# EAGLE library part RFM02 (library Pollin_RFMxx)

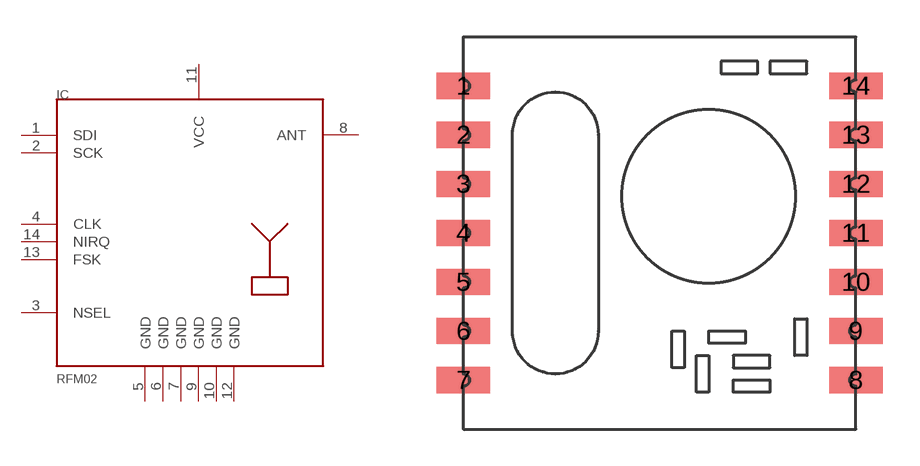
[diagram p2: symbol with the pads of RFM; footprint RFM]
Designator prefix IC

## RFM02  [RFM]
1  SDI
2  SCK
3  NSEL
4  CLK
5  GND
6  GND  pwr
7  GND  pwr
8  ANT  out
9  GND
10  GND
11  VCC  pwr
12  GND
13  FSK
14  NIRQ

## Footprint RFM (pad centres in mm)
smd 2.184 x 1.067: 1 0,14; 2 0,12; 3 0,10; 4 0,8; 5 0,6; 6 0,4; 7 0,2; 8 16,2; 9 16,4; 10 16,6; 11 16,8; 12 16,10; 13 16,12; 14 16,14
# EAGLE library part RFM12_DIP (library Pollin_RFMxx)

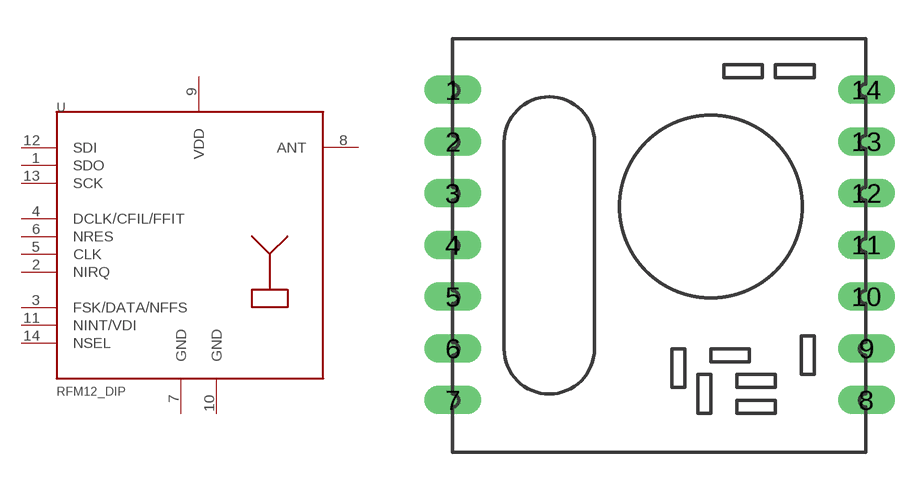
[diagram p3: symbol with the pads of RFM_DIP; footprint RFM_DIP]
Designator prefix -

## RFM12_DIP  [RFM_DIP]
1  SDO
2  NIRQ
3  FSK/DATA/NFFS
4  DCLK/CFIL/FFIT
5  CLK
6  NRES
7  GND  pwr
8  ANT  out
9  VDD  pwr
10  GND  pwr
11  NINT/VDI
12  SDI
13  SCK
14  NSEL

## Footprint RFM_DIP (pad centres in mm)
drill 0.6 long: 1 -8,6; 2 -8,4; 3 -8,2; 4 -8,0; 5 -8,-2; 6 -8,-4; 7 -8,-6; 8 8,-6; 9 8,-4; 10 8,-2; 11 8,0; 12 8,2; 13 8,4; 14 8,6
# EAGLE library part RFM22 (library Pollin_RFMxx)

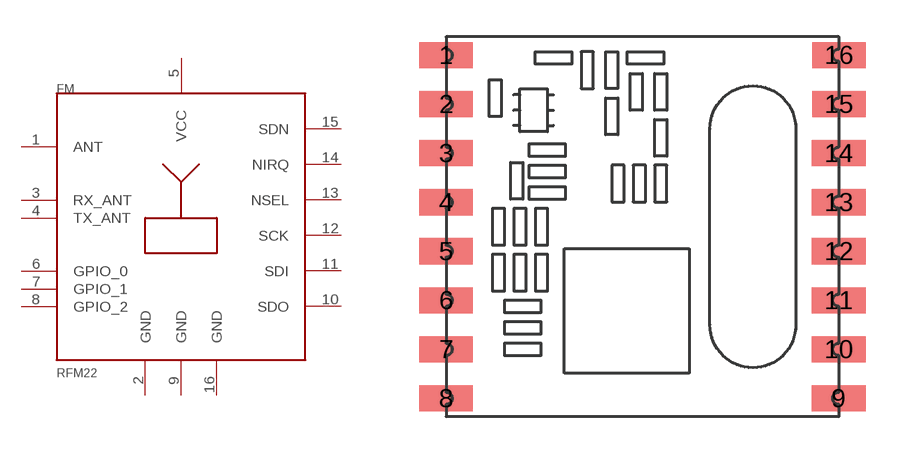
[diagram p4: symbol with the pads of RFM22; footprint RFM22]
Designator prefix FM

## RFM22  [RFM22]
1  ANT
2  GND
3  RX_ANT
4  TX_ANT
5  VCC
6  GPIO_0
7  GPIO_1
8  GPIO_2
9  GND
10  SDO
11  SDI
12  SCK
13  NSEL
14  NIRQ
15  SDN
16  GND

## Footprint RFM22 (pad centres in mm)
smd 2.184 x 1.067: 1 -8.38,5.62; 2 -8.38,3.62; 3 -8.38,1.62; 4 -8.38,-0.38; 5 -8.38,-2.38; 6 -8.38,-4.38; 7 -8.38,-6.38; 8 -8.38,-8.38; 9 7.62,-8.38; 10 7.62,-6.38; 11 7.62,-4.38; 12 7.62,-2.38; 13 7.62,-0.38; 14 7.62,1.62; 15 7.625,3.625; 16 7.625,5.625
